VERSION 5.7 ;
BUSBITCHARS "[]" ;
DIVIDERCHAR "/" ;

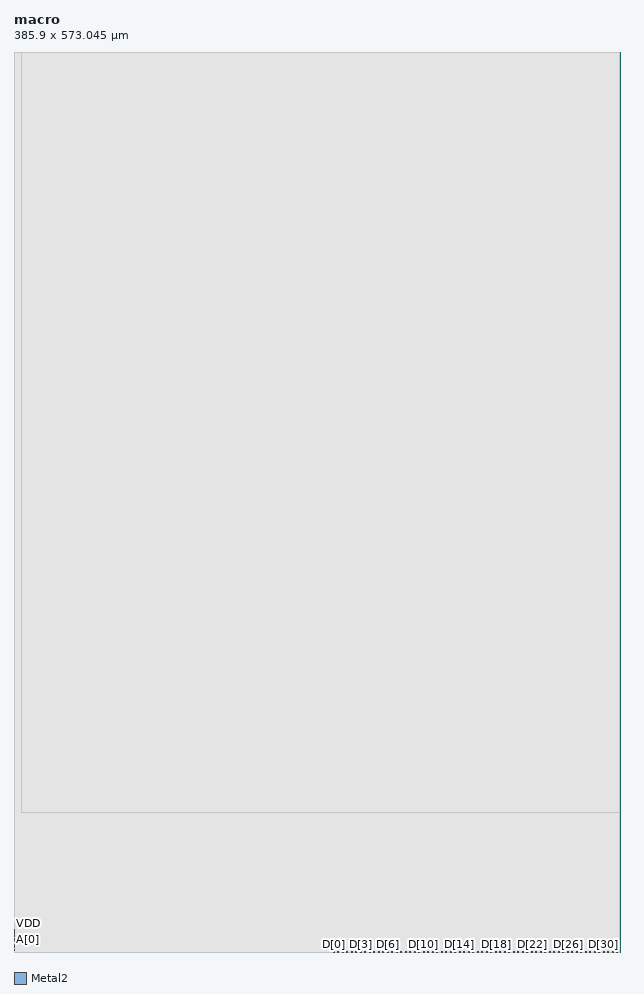
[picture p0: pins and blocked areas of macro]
MACRO macro
  CLASS BLOCK ;
  FOREIGN macro 0 0 ;
  ORIGIN 0 0 ;
  SIZE 385.9000 BY 573.0450 ;
  PIN A[0]
    DIRECTION INPUT ;
    USE SIGNAL ;
    PORT
      LAYER Metal2 ;
        RECT 0.0000 8.0000 0.5000 8.5000 ;
    END
  END A[0]
  PIN A[1]
    DIRECTION INPUT ;
    USE SIGNAL ;
    PORT
      LAYER Metal2 ;
        RECT 0.0000 7.0000 0.5000 7.5000 ;
    END
  END A[1]
  PIN A[2]
    DIRECTION INPUT ;
    USE SIGNAL ;
    PORT
      LAYER Metal2 ;
        RECT 0.0000 6.0000 0.5000 6.5000 ;
    END
  END A[2]
  PIN A[3]
    DIRECTION INPUT ;
    USE SIGNAL ;
    PORT
      LAYER Metal2 ;
        RECT 0.0000 5.0000 0.5000 5.5000 ;
    END
  END A[3]
  PIN A[4]
    DIRECTION INPUT ;
    USE SIGNAL ;
    PORT
      LAYER Metal2 ;
        RECT 0.0000 4.0000 0.5000 4.5000 ;
    END
  END A[4]
  PIN A[5]
    DIRECTION INPUT ;
    USE SIGNAL ;
    PORT
      LAYER Metal2 ;
        RECT 0.0000 3.0000 0.5000 3.5000 ;
    END
  END A[5]
  PIN A[6]
    DIRECTION INPUT ;
    USE SIGNAL ;
    PORT
      LAYER Metal2 ;
        RECT 0.0000 2.0000 0.5000 2.5000 ;
    END
  END A[6]
  PIN A[7]
    DIRECTION INPUT ;
    USE SIGNAL ;
    PORT
      LAYER Metal2 ;
        RECT 0.0000 1.0000 0.5000 1.5000 ;
    END
  END A[7]
  PIN CEN
    DIRECTION INPUT ;
    USE SIGNAL ;
    PORT
      LAYER Metal2 ;
        RECT 0.0000 9.0000 0.5000 9.5000 ;
    END
  END CEN
  PIN CLK
    DIRECTION INPUT ;
    USE CLOCK ;
    PORT
      LAYER Metal2 ;
        RECT 0.0000 10.0000 0.5000 10.5000 ;
    END
  END CLK
  PIN D[0]
    DIRECTION INPUT ;
    USE SIGNAL ;
    PORT
      LAYER Metal2 ;
        RECT 203.3500 0.0000 203.8500 0.5000 ;
    END
  END D[0]
  PIN D[10]
    DIRECTION INPUT ;
    USE SIGNAL ;
    PORT
      LAYER Metal2 ;
        RECT 260.7500 0.0000 261.2500 0.5000 ;
    END
  END D[10]
  PIN D[11]
    DIRECTION INPUT ;
    USE SIGNAL ;
    PORT
      LAYER Metal2 ;
        RECT 266.4900 0.0000 266.9900 0.5000 ;
    END
  END D[11]
  PIN D[12]
    DIRECTION INPUT ;
    USE SIGNAL ;
    PORT
      LAYER Metal2 ;
        RECT 272.2300 0.0000 272.7300 0.5000 ;
    END
  END D[12]
  PIN D[13]
    DIRECTION INPUT ;
    USE SIGNAL ;
    PORT
      LAYER Metal2 ;
        RECT 277.9700 0.0000 278.4700 0.5000 ;
    END
  END D[13]
  PIN D[14]
    DIRECTION INPUT ;
    USE SIGNAL ;
    PORT
      LAYER Metal2 ;
        RECT 283.7100 0.0000 284.2100 0.5000 ;
    END
  END D[14]
  PIN D[15]
    DIRECTION INPUT ;
    USE SIGNAL ;
    PORT
      LAYER Metal2 ;
        RECT 289.4500 0.0000 289.9500 0.5000 ;
    END
  END D[15]
  PIN D[16]
    DIRECTION INPUT ;
    USE SIGNAL ;
    PORT
      LAYER Metal2 ;
        RECT 295.1900 0.0000 295.6900 0.5000 ;
    END
  END D[16]
  PIN D[17]
    DIRECTION INPUT ;
    USE SIGNAL ;
    PORT
      LAYER Metal2 ;
        RECT 300.9300 0.0000 301.4300 0.5000 ;
    END
  END D[17]
  PIN D[18]
    DIRECTION INPUT ;
    USE SIGNAL ;
    PORT
      LAYER Metal2 ;
        RECT 306.6700 0.0000 307.1700 0.5000 ;
    END
  END D[18]
  PIN D[19]
    DIRECTION INPUT ;
    USE SIGNAL ;
    PORT
      LAYER Metal2 ;
        RECT 312.4100 0.0000 312.9100 0.5000 ;
    END
  END D[19]
  PIN D[1]
    DIRECTION INPUT ;
    USE SIGNAL ;
    PORT
      LAYER Metal2 ;
        RECT 209.0900 0.0000 209.5900 0.5000 ;
    END
  END D[1]
  PIN D[20]
    DIRECTION INPUT ;
    USE SIGNAL ;
    PORT
      LAYER Metal2 ;
        RECT 318.1500 0.0000 318.6500 0.5000 ;
    END
  END D[20]
  PIN D[21]
    DIRECTION INPUT ;
    USE SIGNAL ;
    PORT
      LAYER Metal2 ;
        RECT 323.8900 0.0000 324.3900 0.5000 ;
    END
  END D[21]
  PIN D[22]
    DIRECTION INPUT ;
    USE SIGNAL ;
    PORT
      LAYER Metal2 ;
        RECT 329.6300 0.0000 330.1300 0.5000 ;
    END
  END D[22]
  PIN D[23]
    DIRECTION INPUT ;
    USE SIGNAL ;
    PORT
      LAYER Metal2 ;
        RECT 335.3700 0.0000 335.8700 0.5000 ;
    END
  END D[23]
  PIN D[24]
    DIRECTION INPUT ;
    USE SIGNAL ;
    PORT
      LAYER Metal2 ;
        RECT 341.1100 0.0000 341.6100 0.5000 ;
    END
  END D[24]
  PIN D[25]
    DIRECTION INPUT ;
    USE SIGNAL ;
    PORT
      LAYER Metal2 ;
        RECT 346.8500 0.0000 347.3500 0.5000 ;
    END
  END D[25]
  PIN D[26]
    DIRECTION INPUT ;
    USE SIGNAL ;
    PORT
      LAYER Metal2 ;
        RECT 352.5900 0.0000 353.0900 0.5000 ;
    END
  END D[26]
  PIN D[27]
    DIRECTION INPUT ;
    USE SIGNAL ;
    PORT
      LAYER Metal2 ;
        RECT 358.3300 0.0000 358.8300 0.5000 ;
    END
  END D[27]
  PIN D[28]
    DIRECTION INPUT ;
    USE SIGNAL ;
    PORT
      LAYER Metal2 ;
        RECT 364.0700 0.0000 364.5700 0.5000 ;
    END
  END D[28]
  PIN D[29]
    DIRECTION INPUT ;
    USE SIGNAL ;
    PORT
      LAYER Metal2 ;
        RECT 369.8100 0.0000 370.3100 0.5000 ;
    END
  END D[29]
  PIN D[2]
    DIRECTION INPUT ;
    USE SIGNAL ;
    PORT
      LAYER Metal2 ;
        RECT 214.8300 0.0000 215.3300 0.5000 ;
    END
  END D[2]
  PIN D[30]
    DIRECTION INPUT ;
    USE SIGNAL ;
    PORT
      LAYER Metal2 ;
        RECT 375.5500 0.0000 376.0500 0.5000 ;
    END
  END D[30]
  PIN D[31]
    DIRECTION INPUT ;
    USE SIGNAL ;
    PORT
      LAYER Metal2 ;
        RECT 381.2900 0.0000 381.7900 0.5000 ;
    END
  END D[31]
  PIN D[3]
    DIRECTION INPUT ;
    USE SIGNAL ;
    PORT
      LAYER Metal2 ;
        RECT 220.5700 0.0000 221.0700 0.5000 ;
    END
  END D[3]
  PIN D[4]
    DIRECTION INPUT ;
    USE SIGNAL ;
    PORT
      LAYER Metal2 ;
        RECT 226.3100 0.0000 226.8100 0.5000 ;
    END
  END D[4]
  PIN D[5]
    DIRECTION INPUT ;
    USE SIGNAL ;
    PORT
      LAYER Metal2 ;
        RECT 232.0500 0.0000 232.5500 0.5000 ;
    END
  END D[5]
  PIN D[6]
    DIRECTION INPUT ;
    USE SIGNAL ;
    PORT
      LAYER Metal2 ;
        RECT 237.7900 0.0000 238.2900 0.5000 ;
    END
  END D[6]
  PIN D[7]
    DIRECTION INPUT ;
    USE SIGNAL ;
    PORT
      LAYER Metal2 ;
        RECT 243.5300 0.0000 244.0300 0.5000 ;
    END
  END D[7]
  PIN D[8]
    DIRECTION INPUT ;
    USE SIGNAL ;
    PORT
      LAYER Metal2 ;
        RECT 249.2700 0.0000 249.7700 0.5000 ;
    END
  END D[8]
  PIN D[9]
    DIRECTION INPUT ;
    USE SIGNAL ;
    PORT
      LAYER Metal2 ;
        RECT 255.0100 0.0000 255.5100 0.5000 ;
    END
  END D[9]
  PIN GWEN
    DIRECTION INPUT ;
    USE SIGNAL ;
    PORT
      LAYER Metal2 ;
        RECT 0.0000 11.0000 0.5000 11.5000 ;
    END
  END GWEN
  PIN Q[0]
    DIRECTION OUTPUT ;
    USE SIGNAL ;
    PORT
      LAYER Metal2 ;
        RECT 205.8500 0.0000 206.3500 0.5000 ;
    END
  END Q[0]
  PIN Q[10]
    DIRECTION OUTPUT ;
    USE SIGNAL ;
    PORT
      LAYER Metal2 ;
        RECT 263.2500 0.0000 263.7500 0.5000 ;
    END
  END Q[10]
  PIN Q[11]
    DIRECTION OUTPUT ;
    USE SIGNAL ;
    PORT
      LAYER Metal2 ;
        RECT 268.9900 0.0000 269.4900 0.5000 ;
    END
  END Q[11]
  PIN Q[12]
    DIRECTION OUTPUT ;
    USE SIGNAL ;
    PORT
      LAYER Metal2 ;
        RECT 274.7300 0.0000 275.2300 0.5000 ;
    END
  END Q[12]
  PIN Q[13]
    DIRECTION OUTPUT ;
    USE SIGNAL ;
    PORT
      LAYER Metal2 ;
        RECT 280.4700 0.0000 280.9700 0.5000 ;
    END
  END Q[13]
  PIN Q[14]
    DIRECTION OUTPUT ;
    USE SIGNAL ;
    PORT
      LAYER Metal2 ;
        RECT 286.2100 0.0000 286.7100 0.5000 ;
    END
  END Q[14]
  PIN Q[15]
    DIRECTION OUTPUT ;
    USE SIGNAL ;
    PORT
      LAYER Metal2 ;
        RECT 291.9500 0.0000 292.4500 0.5000 ;
    END
  END Q[15]
  PIN Q[16]
    DIRECTION OUTPUT ;
    USE SIGNAL ;
    PORT
      LAYER Metal2 ;
        RECT 297.6900 0.0000 298.1900 0.5000 ;
    END
  END Q[16]
  PIN Q[17]
    DIRECTION OUTPUT ;
    USE SIGNAL ;
    PORT
      LAYER Metal2 ;
        RECT 303.4300 0.0000 303.9300 0.5000 ;
    END
  END Q[17]
  PIN Q[18]
    DIRECTION OUTPUT ;
    USE SIGNAL ;
    PORT
      LAYER Metal2 ;
        RECT 309.1700 0.0000 309.6700 0.5000 ;
    END
  END Q[18]
  PIN Q[19]
    DIRECTION OUTPUT ;
    USE SIGNAL ;
    PORT
      LAYER Metal2 ;
        RECT 314.9100 0.0000 315.4100 0.5000 ;
    END
  END Q[19]
  PIN Q[1]
    DIRECTION OUTPUT ;
    USE SIGNAL ;
    PORT
      LAYER Metal2 ;
        RECT 211.5900 0.0000 212.0900 0.5000 ;
    END
  END Q[1]
  PIN Q[20]
    DIRECTION OUTPUT ;
    USE SIGNAL ;
    PORT
      LAYER Metal2 ;
        RECT 320.6500 0.0000 321.1500 0.5000 ;
    END
  END Q[20]
  PIN Q[21]
    DIRECTION OUTPUT ;
    USE SIGNAL ;
    PORT
      LAYER Metal2 ;
        RECT 326.3900 0.0000 326.8900 0.5000 ;
    END
  END Q[21]
  PIN Q[22]
    DIRECTION OUTPUT ;
    USE SIGNAL ;
    PORT
      LAYER Metal2 ;
        RECT 332.1300 0.0000 332.6300 0.5000 ;
    END
  END Q[22]
  PIN Q[23]
    DIRECTION OUTPUT ;
    USE SIGNAL ;
    PORT
      LAYER Metal2 ;
        RECT 337.8700 0.0000 338.3700 0.5000 ;
    END
  END Q[23]
  PIN Q[24]
    DIRECTION OUTPUT ;
    USE SIGNAL ;
    PORT
      LAYER Metal2 ;
        RECT 343.6100 0.0000 344.1100 0.5000 ;
    END
  END Q[24]
  PIN Q[25]
    DIRECTION OUTPUT ;
    USE SIGNAL ;
    PORT
      LAYER Metal2 ;
        RECT 349.3500 0.0000 349.8500 0.5000 ;
    END
  END Q[25]
  PIN Q[26]
    DIRECTION OUTPUT ;
    USE SIGNAL ;
    PORT
      LAYER Metal2 ;
        RECT 355.0900 0.0000 355.5900 0.5000 ;
    END
  END Q[26]
  PIN Q[27]
    DIRECTION OUTPUT ;
    USE SIGNAL ;
    PORT
      LAYER Metal2 ;
        RECT 360.8300 0.0000 361.3300 0.5000 ;
    END
  END Q[27]
  PIN Q[28]
    DIRECTION OUTPUT ;
    USE SIGNAL ;
    PORT
      LAYER Metal2 ;
        RECT 366.5700 0.0000 367.0700 0.5000 ;
    END
  END Q[28]
  PIN Q[29]
    DIRECTION OUTPUT ;
    USE SIGNAL ;
    PORT
      LAYER Metal2 ;
        RECT 372.3100 0.0000 372.8100 0.5000 ;
    END
  END Q[29]
  PIN Q[2]
    DIRECTION OUTPUT ;
    USE SIGNAL ;
    PORT
      LAYER Metal2 ;
        RECT 217.3300 0.0000 217.8300 0.5000 ;
    END
  END Q[2]
  PIN Q[30]
    DIRECTION OUTPUT ;
    USE SIGNAL ;
    PORT
      LAYER Metal2 ;
        RECT 378.0500 0.0000 378.5500 0.5000 ;
    END
  END Q[30]
  PIN Q[31]
    DIRECTION OUTPUT ;
    USE SIGNAL ;
    PORT
      LAYER Metal2 ;
        RECT 383.7900 0.0000 384.2900 0.5000 ;
    END
  END Q[31]
  PIN Q[3]
    DIRECTION OUTPUT ;
    USE SIGNAL ;
    PORT
      LAYER Metal2 ;
        RECT 223.0700 0.0000 223.5700 0.5000 ;
    END
  END Q[3]
  PIN Q[4]
    DIRECTION OUTPUT ;
    USE SIGNAL ;
    PORT
      LAYER Metal2 ;
        RECT 228.8100 0.0000 229.3100 0.5000 ;
    END
  END Q[4]
  PIN Q[5]
    DIRECTION OUTPUT ;
    USE SIGNAL ;
    PORT
      LAYER Metal2 ;
        RECT 234.5500 0.0000 235.0500 0.5000 ;
    END
  END Q[5]
  PIN Q[6]
    DIRECTION OUTPUT ;
    USE SIGNAL ;
    PORT
      LAYER Metal2 ;
        RECT 240.2900 0.0000 240.7900 0.5000 ;
    END
  END Q[6]
  PIN Q[7]
    DIRECTION OUTPUT ;
    USE SIGNAL ;
    PORT
      LAYER Metal2 ;
        RECT 246.0300 0.0000 246.5300 0.5000 ;
    END
  END Q[7]
  PIN Q[8]
    DIRECTION OUTPUT ;
    USE SIGNAL ;
    PORT
      LAYER Metal2 ;
        RECT 251.7700 0.0000 252.2700 0.5000 ;
    END
  END Q[8]
  PIN Q[9]
    DIRECTION OUTPUT ;
    USE SIGNAL ;
    PORT
      LAYER Metal2 ;
        RECT 257.5100 0.0000 258.0100 0.5000 ;
    END
  END Q[9]
  PIN VDD
    DIRECTION INOUT ;
    USE POWER ;
    PORT
      LAYER Metal2 ;
        RECT 0.0000 13.0000 0.5000 13.5000 ;
    END
  END VDD
  PIN VSS
    DIRECTION INOUT ;
    USE GROUND ;
    PORT
      LAYER Metal2 ;
        RECT 0.0000 14.0000 0.5000 14.5000 ;
    END
  END VSS
  PIN WEN
    DIRECTION INPUT ;
    USE SIGNAL ;
    PORT
      LAYER Metal2 ;
        RECT 0.0000 12.0000 0.5000 12.5000 ;
    END
  END WEN
  OBS
    LAYER Metal1 ;
        RECT 0.0500 0.2100 385.5100 572.9700 ;
  END
  OBS
    LAYER Metal2 ;
        POLYGON 0.0000 0.0000 0.0000 1.0000 0.5000 1.0000 0.5000 1.5000 0.0000 1.5000 0.0000 2.0000 0.5000 2.0000 0.5000 2.5000 0.0000 2.5000 0.0000 3.0000 0.5000 3.0000 0.5000 3.5000 0.0000 3.5000 0.0000 4.0000 0.5000 4.0000 0.5000 4.5000 0.0000 4.5000 0.0000 5.0000 0.5000 5.0000 0.5000 5.5000 0.0000 5.5000 0.0000 6.0000 0.5000 6.0000 0.5000 6.5000 0.0000 6.5000 0.0000 7.0000 0.5000 7.0000 0.5000 7.5000 0.0000 7.5000 0.0000 8.0000 0.5000 8.0000 0.5000 8.5000 0.0000 8.5000 0.0000 9.0000 0.5000 9.0000 0.5000 9.5000 0.0000 9.5000 0.0000 10.0000 0.5000 10.0000 0.5000 10.5000 0.0000 10.5000 0.0000 11.0000 0.5000 11.0000 0.5000 11.5000 0.0000 11.5000 0.0000 12.0000 0.5000 12.0000 0.5000 12.5000 0.0000 12.5000 0.0000 13.0000 0.5000 13.0000 0.5000 13.5000 0.0000 13.5000 0.0000 14.0000 0.5000 14.0000 0.5000 14.5000 0.0000 14.5000 0.0000 572.4900 385.5050 572.4900 385.5050 0.0000 384.2900 0.0000 384.2900 0.5000 383.7900 0.5000 383.7900 0.0000 381.7900 0.0000 381.7900 0.5000 381.2900 0.5000 381.2900 0.0000 378.5500 0.0000 378.5500 0.5000 378.0500 0.5000 378.0500 0.0000 376.0500 0.0000 376.0500 0.5000 375.5500 0.5000 375.5500 0.0000 372.8100 0.0000 372.8100 0.5000 372.3100 0.5000 372.3100 0.0000 370.3100 0.0000 370.3100 0.5000 369.8100 0.5000 369.8100 0.0000 367.0700 0.0000 367.0700 0.5000 366.5700 0.5000 366.5700 0.0000 364.5700 0.0000 364.5700 0.5000 364.0700 0.5000 364.0700 0.0000 361.3300 0.0000 361.3300 0.5000 360.8300 0.5000 360.8300 0.0000 358.8300 0.0000 358.8300 0.5000 358.3300 0.5000 358.3300 0.0000 355.5900 0.0000 355.5900 0.5000 355.0900 0.5000 355.0900 0.0000 353.0900 0.0000 353.0900 0.5000 352.5900 0.5000 352.5900 0.0000 349.8500 0.0000 349.8500 0.5000 349.3500 0.5000 349.3500 0.0000 347.3500 0.0000 347.3500 0.5000 346.8500 0.5000 346.8500 0.0000 344.1100 0.0000 344.1100 0.5000 343.6100 0.5000 343.6100 0.0000 341.6100 0.0000 341.6100 0.5000 341.1100 0.5000 341.1100 0.0000 338.3700 0.0000 338.3700 0.5000 337.8700 0.5000 337.8700 0.0000 335.8700 0.0000 335.8700 0.5000 335.3700 0.5000 335.3700 0.0000 332.6300 0.0000 332.6300 0.5000 332.1300 0.5000 332.1300 0.0000 330.1300 0.0000 330.1300 0.5000 329.6300 0.5000 329.6300 0.0000 326.8900 0.0000 326.8900 0.5000 326.3900 0.5000 326.3900 0.0000 324.3900 0.0000 324.3900 0.5000 323.8900 0.5000 323.8900 0.0000 321.1500 0.0000 321.1500 0.5000 320.6500 0.5000 320.6500 0.0000 318.6500 0.0000 318.6500 0.5000 318.1500 0.5000 318.1500 0.0000 315.4100 0.0000 315.4100 0.5000 314.9100 0.5000 314.9100 0.0000 312.9100 0.0000 312.9100 0.5000 312.4100 0.5000 312.4100 0.0000 309.6700 0.0000 309.6700 0.5000 309.1700 0.5000 309.1700 0.0000 307.1700 0.0000 307.1700 0.5000 306.6700 0.5000 306.6700 0.0000 303.9300 0.0000 303.9300 0.5000 303.4300 0.5000 303.4300 0.0000 301.4300 0.0000 301.4300 0.5000 300.9300 0.5000 300.9300 0.0000 298.1900 0.0000 298.1900 0.5000 297.6900 0.5000 297.6900 0.0000 295.6900 0.0000 295.6900 0.5000 295.1900 0.5000 295.1900 0.0000 292.4500 0.0000 292.4500 0.5000 291.9500 0.5000 291.9500 0.0000 289.9500 0.0000 289.9500 0.5000 289.4500 0.5000 289.4500 0.0000 286.7100 0.0000 286.7100 0.5000 286.2100 0.5000 286.2100 0.0000 284.2100 0.0000 284.2100 0.5000 283.7100 0.5000 283.7100 0.0000 280.9700 0.0000 280.9700 0.5000 280.4700 0.5000 280.4700 0.0000 278.4700 0.0000 278.4700 0.5000 277.9700 0.5000 277.9700 0.0000 275.2300 0.0000 275.2300 0.5000 274.7300 0.5000 274.7300 0.0000 272.7300 0.0000 272.7300 0.5000 272.2300 0.5000 272.2300 0.0000 269.4900 0.0000 269.4900 0.5000 268.9900 0.5000 268.9900 0.0000 266.9900 0.0000 266.9900 0.5000 266.4900 0.5000 266.4900 0.0000 263.7500 0.0000 263.7500 0.5000 263.2500 0.5000 263.2500 0.0000 261.2500 0.0000 261.2500 0.5000 260.7500 0.5000 260.7500 0.0000 258.0100 0.0000 258.0100 0.5000 257.5100 0.5000 257.5100 0.0000 255.5100 0.0000 255.5100 0.5000 255.0100 0.5000 255.0100 0.0000 252.2700 0.0000 252.2700 0.5000 251.7700 0.5000 251.7700 0.0000 249.7700 0.0000 249.7700 0.5000 249.2700 0.5000 249.2700 0.0000 246.5300 0.0000 246.5300 0.5000 246.0300 0.5000 246.0300 0.0000 244.0300 0.0000 244.0300 0.5000 243.5300 0.5000 243.5300 0.0000 240.7900 0.0000 240.7900 0.5000 240.2900 0.5000 240.2900 0.0000 238.2900 0.0000 238.2900 0.5000 237.7900 0.5000 237.7900 0.0000 235.0500 0.0000 235.0500 0.5000 234.5500 0.5000 234.5500 0.0000 232.5500 0.0000 232.5500 0.5000 232.0500 0.5000 232.0500 0.0000 229.3100 0.0000 229.3100 0.5000 228.8100 0.5000 228.8100 0.0000 226.8100 0.0000 226.8100 0.5000 226.3100 0.5000 226.3100 0.0000 223.5700 0.0000 223.5700 0.5000 223.0700 0.5000 223.0700 0.0000 221.0700 0.0000 221.0700 0.5000 220.5700 0.5000 220.5700 0.0000 217.8300 0.0000 217.8300 0.5000 217.3300 0.5000 217.3300 0.0000 215.3300 0.0000 215.3300 0.5000 214.8300 0.5000 214.8300 0.0000 212.0900 0.0000 212.0900 0.5000 211.5900 0.5000 211.5900 0.0000 209.5900 0.0000 209.5900 0.5000 209.0900 0.5000 209.0900 0.0000 206.3500 0.0000 206.3500 0.5000 205.8500 0.5000 205.8500 0.0000 203.8500 0.0000 203.8500 0.5000 203.3500 0.5000 203.3500 0.0000 ;
  END
  OBS
    LAYER Metal3 ;
        RECT 5.0600 88.7900 385.5050 572.4900 ;
  END
END macro
END LIBRARY
